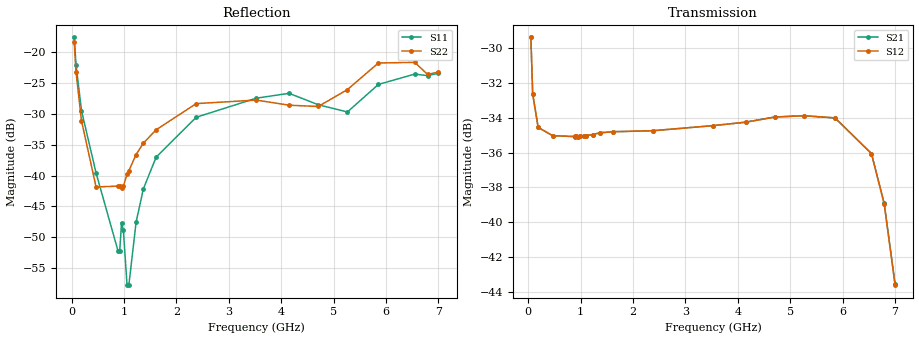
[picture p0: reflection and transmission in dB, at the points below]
! Integrated Device Technology
! Corporate Headquarters
! 6024 Silver Creek Valley Road
! San Jose, CA 95138  USA
! Phone:  1-408-284-8200
! Toll Free:  1-800-223-1366
! Webpage:  http://www.idt.com/
! Timing and RF Division
! 515 Groton Road, Suite 102
! Westford, MA 01886-6024
! Device:  F2258
! Description: Voltage Variable RF Attenuator
! Frequency:  50.0 -  6000.00 MHz
! Package:  3x3 mm Thin QFN Plastic Package: 16 pin
! Ports:  2 RF, 2 DC
!  Pin  1  = NC
!  Pin  2  = NC
!  Pin  3  = RF2  = Port 2
!  Pin  4  = GND
!  Pin  5  = Vdd
!  Pin  6  = NC
!  Pin  7  = VCTRL
!  Pin  8  = NC
!  Pin  9  = GND
!  Pin 10  = RF1  = Port 1
!  Pin 11  = NC
!  Pin 12  = NC
!  Pin 13  = NC
!  Pin 14  = NC
!  Pin 15  = NC
!  Pin 16  = NC
! Vcntrl:  2.030 Volts
! Vdd:  +3.300 Volts
! Current:  1.153 mA
! Data:  The device was measured on a the F2258 evaluation board which has
!  individual transmission lines to the RF pins.  Data was collected
!  using a calibrated network analyzer.  The evaluation board was
!  de-embedded using a TRL calibration technique.
!  The reference plane is the edge of the package pin.
! Misc:  SN 10
!  Action Tracker AT0285
! Date Measured:  2014-12-10
! Date:  2016-01-13  MJV
! Note:
!  Integrated Device Technology supplies this data as a sample of measured
!  data at the package pin for this product.  Your particular data for this
!  product may vary.
!  Data was taken at 25 degrees C.
!  Integrated Device Technology reserves the right to change this data at anytime.
!Freq_(GHz)  S11M_(dB)  S11P_(deg)  S21M_(dB)  S21P_(deg)  S12M_(dB)  S12P_(deg)  S22M_(dB)  S22P_(deg)
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# GHz S dB R 50
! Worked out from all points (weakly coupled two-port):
!   201 points, 50 MHz to 7 GHz, reference 50 ohm
!   highest |S21| = -29.38 dB at 50 MHz (marker M1); lowest = -43.6 dB at 7 GHz (marker M2)
!   lowest |S11| = -57.8 dB at 1.093 GHz (marker M3), VSWR 1.00, Z = 49.9 + j0.113 ohm
!   |S11| at or under -10 dB: start of sweep to end of sweep
!   |S22| runs from -43.0 to -18.4 dB; largest |S21 - S12| = 6.9e-05
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0.05  -17.55 -110.9  -29.38 -67.0  -29.38 -67.0  -18.36 -108.8
0.08475  -21.98 -107.4  -32.63 -47.5  -32.63 -47.5  -23.19 -100.8
0.189  -29.43 -109.4  -34.55 -24.1  -34.55 -24.1  -31.07 -90.0
0.467  -39.55 -120.2  -35.03 -11.7  -35.03 -11.7  -41.83 -42.4
0.884  -52.16 166.6  -35.08 -8.6  -35.07 -8.6  -41.70 26.3
0.91875  -52.15 150.1  -35.07 -8.5  -35.07 -8.5  -41.60 28.8
0.9535  -47.61 -162.1  -35.08 -8.4  -35.08 -8.4  -41.97 52.7
0.98825  -48.83 -173.7  -35.06 -8.3  -35.06 -8.4  -41.71 48.8
1.05775  -57.75 154.9  -35.05 -8.2  -35.04 -8.2  -39.75 42.8
1.0925  -57.77 118.5  -35.03 -8.2  -35.03 -8.2  -39.19 41.7
1.2315  -47.51 46.4  -34.96 -8.3  -34.96 -8.3  -36.58 34.7
1.3705  -42.13 36.5  -34.86 -8.8  -34.86 -8.8  -34.71 31.9
1.61375  -36.99 32.6  -34.80 -10.1  -34.80 -10.1  -32.55 28.0
2.37825  -30.52 48.1  -34.74 -13.8  -34.74 -13.8  -28.30 28.0
3.525  -27.42 91.5  -34.45 -20.5  -34.45 -20.5  -27.73 55.0
4.1505  -26.63 105.0  -34.25 -25.1  -34.25 -25.1  -28.56 64.8
4.7065  -28.49 95.6  -33.95 -29.8  -33.96 -29.7  -28.77 46.6
5.2625  -29.66 54.3  -33.88 -35.9  -33.88 -35.9  -26.03 10.0
5.85325  -25.19 29.8  -34.01 -46.4  -34.00 -46.4  -21.71 -9.3
6.54825  -23.51 45.0  -36.05 -66.6  -36.06 -66.6  -21.60 -43.2
6.7915  -23.76 63.2  -38.92 -73.2  -38.94 -73.0  -23.56 -77.7
7  -23.38 84.4  -43.57 -62.2  -43.61 -61.9  -23.19 -128.2
